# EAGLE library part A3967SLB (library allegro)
MICROSTEPPING DRIVER WITH TRANSLATOR Source: 3967.pdf

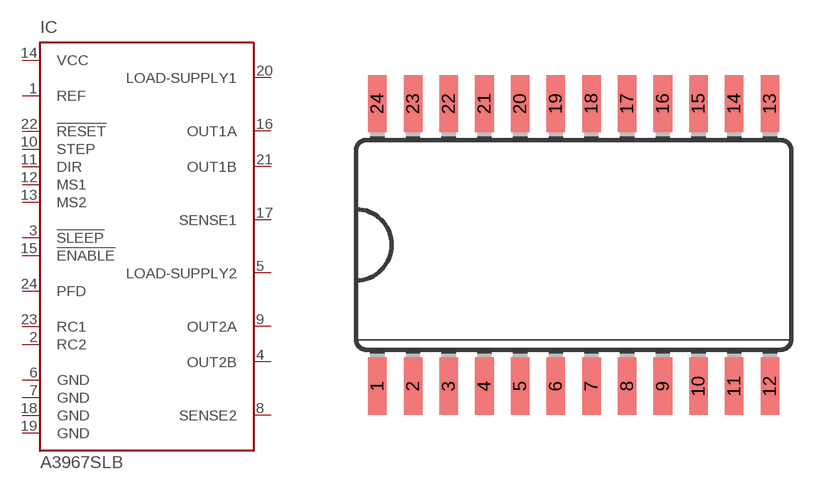
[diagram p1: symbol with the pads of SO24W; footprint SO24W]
Designator prefix IC

## A3967SLB (MF: ALLEGRO MICROSYSTEMS, INC.; MPN: A3967SLB-T; OC_FARNELL: 1521715; OC_NEWARK: 08J5877)  [SO24W]
1  REF  in
2  RC2  in
3  !SLEEP  in
4  OUT2B  out
5  LOAD-SUPPLY2  in
6  GND  pwr
7  GND  pwr
8  SENSE2  in
9  OUT2A  out
10  STEP  in
11  DIR  in
12  MS1  in
13  MS2  in
14  VCC  pwr
15  !ENABLE  in
16  OUT1A  out
17  SENSE1  in
18  GND  pwr
19  GND  pwr
20  LOAD-SUPPLY1  in
21  OUT1B  out
22  !RESET  in
23  RC1  in
24  PFD  in

## Footprint SO24W (pad centres in mm)
Small Outline Package 24 wide
smd 0.66 x 2.032: 1 -6.985,-5.029; 2 -5.715,-5.029; 3 -4.445,-5.029; 4 -3.175,-5.029; 5 -1.905,-5.029; 6 -0.635,-5.029; 7 0.635,-5.029; 8 1.905,-5.029; 9 3.175,-5.029; 10 4.445,-5.029; 11 5.715,-5.029; 12 6.985,-5.029; 13 6.985,5.029; 14 5.715,5.029; 15 4.445,5.029; 16 3.175,5.029; 17 1.905,5.029; 18 0.635,5.029; 19 -0.635,5.029; 20 -1.905,5.029; 21 -3.175,5.029; 22 -4.445,5.029; 23 -5.715,5.029; 24 -6.985,5.029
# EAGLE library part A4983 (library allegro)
DMOS Microstepping Driver with Translator Auto generated by make-symbol-device-package-bsdl.ulp Rev. 32 Source: http://www.allegromicro.com/en/Products/Part_Numbers/4983/4983.pdf

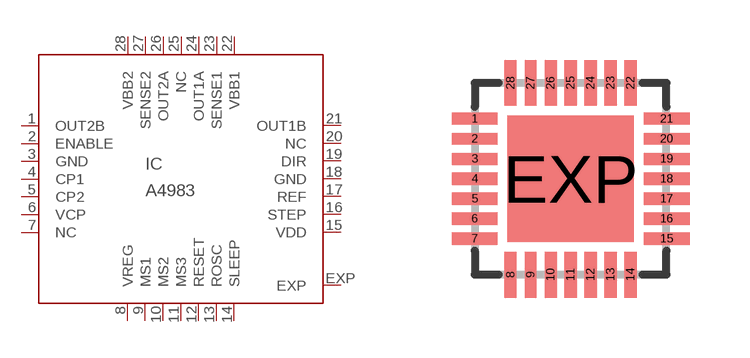
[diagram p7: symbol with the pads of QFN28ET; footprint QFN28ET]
Designator prefix IC

## A4983 (MPN: A4983SETTR-T; OC_FARNELL: 1688956; OC_NEWARK: 39M6763)  [QFN28ET]
1  OUT2B  out
2  ENABLE  in
3  GND  pwr
4  CP1  pas
5  CP2  pas
6  VCP  pas
7  NC  nc
8  VREG  pas
9  MS1  in
10  MS2  in
11  MS3  in
12  RESET  in
13  ROSC  in
14  SLEEP  in
15  VDD  pwr
16  STEP  in
17  REF  in
18  GND  pwr
19  DIR  in
20  NC  nc
21  OUT1B  out
22  VBB1  pwr
23  SENSE1  in
24  OUT1A  out
25  NC  nc
26  OUT2A  out
27  SENSE2  in
28  VBB2  pwr
EXP  EXP  pas

## Footprint QFN28ET (pad centres in mm)
28 Pin QFN ET Auto generated by make-symbol-device-package-bsdl.ulp Rev. 32 Source: http://www.allegromicro.com/en/Products/Part_Numbers/4983/4983.pdf
smd 1.15 x 0.3: 1 -2.4,1.5; 2 -2.4,1; 3 -2.4,0.5; 4 -2.4,0; 5 -2.4,-0.5; 6 -2.4,-1; 7 -2.4,-1.5; 15 2.4,-1.5; 16 2.4,-1; 17 2.4,-0.5; 18 2.4,0; 19 2.4,0.5; 20 2.4,1; 21 2.4,1.5
smd 0.3 x 1.15: 8 -1.5,-2.4; 9 -1,-2.4; 10 -0.5,-2.4; 11 0,-2.4; 12 0.5,-2.4; 13 1,-2.4; 14 1.5,-2.4; 22 1.5,2.4; 23 1,2.4; 24 0.5,2.4; 25 0,2.4; 26 -0.5,2.4; 27 -1,2.4; 28 -1.5,2.4
smd 3.15 x 3.15: EXP 0,0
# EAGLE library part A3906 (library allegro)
Low Voltage Stepper and Single/Dual DC Motor Driver Data Sheet

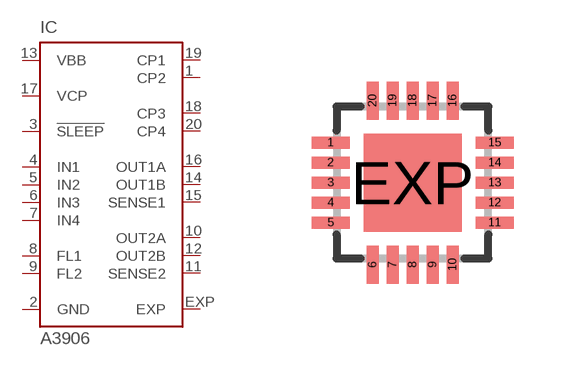
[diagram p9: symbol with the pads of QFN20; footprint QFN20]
Designator prefix IC

## A3906  [QFN20]
1  CP2  pas
2  GND  pwr
3  !SLEEP  in
4  IN1  in
5  IN2  in
6  IN3  in
7  IN4  in
8  FL1  in
9  FL2  in
10  OUT2A  out
11  SENSE2  in
12  OUT2B  out
13  VBB  pwr
14  OUT1B  out
15  SENSE1  in
16  OUT1A  out
17  VCP  pas
18  CP3  pas
19  CP1  pas
20  CP4  pas
EXP  EXP  pas

## Footprint QFN20 (pad centres in mm)
ES Package, 20-Contact QFN with Exposed Thermal Pad Data sheet
smd 0.95 x 0.3: 1 -2.05,1; 2 -2.05,0.5; 3 -2.05,0; 4 -2.05,-0.5; 5 -2.05,-1; 11 2.05,-1; 12 2.05,-0.5; 13 2.05,0; 14 2.05,0.5; 15 2.05,1
smd 0.3 x 0.95: 6 -1,-2.05; 7 -0.5,-2.05; 8 0,-2.05; 9 0.5,-2.05; 10 1,-2.05; 16 1,2.05; 17 0.5,2.05; 18 0,2.05; 19 -0.5,2.05; 20 -1,2.05
smd 2.45 x 2.45: EXP 0,0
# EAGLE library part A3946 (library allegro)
Half-Bridge Power MOSFET Controller Source: Data sheet

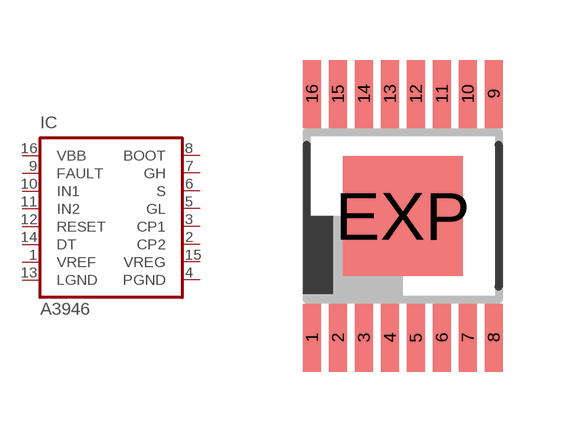
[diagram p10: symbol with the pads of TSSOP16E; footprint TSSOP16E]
Designator prefix IC

## A3946KLP-T, A3946KLPTR-T  [TSSOP16E]
1  VREF  pas
2  CP2  pas
3  CP1  pas
4  PGND  pwr
5  GL  out
6  S  in
7  GH  out
8  BOOT  in
9  FAULT  out
10  IN1  in
11  IN2  in
12  RESET  in
13  LGND  pwr
14  DT  pas
15  VREG  pas
16  VBB  in

## Footprint TSSOP16E (pad centres in mm)
LP Package TSSOP with Exposed Thermal Pad Source: Data sheet
smd 0.45 x 1.7: 1 -2.275,-3.05; 2 -1.625,-3.05; 3 -0.975,-3.05; 4 -0.325,-3.05; 5 0.325,-3.05; 6 0.975,-3.05; 7 1.625,-3.05; 8 2.275,-3.05; 9 2.275,3.05; 10 1.625,3.05; 11 0.975,3.05; 12 0.325,3.05; 13 -0.325,3.05; 14 -0.975,3.05; 15 -1.625,3.05; 16 -2.275,3.05
smd 3 x 3: EXP 0,0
